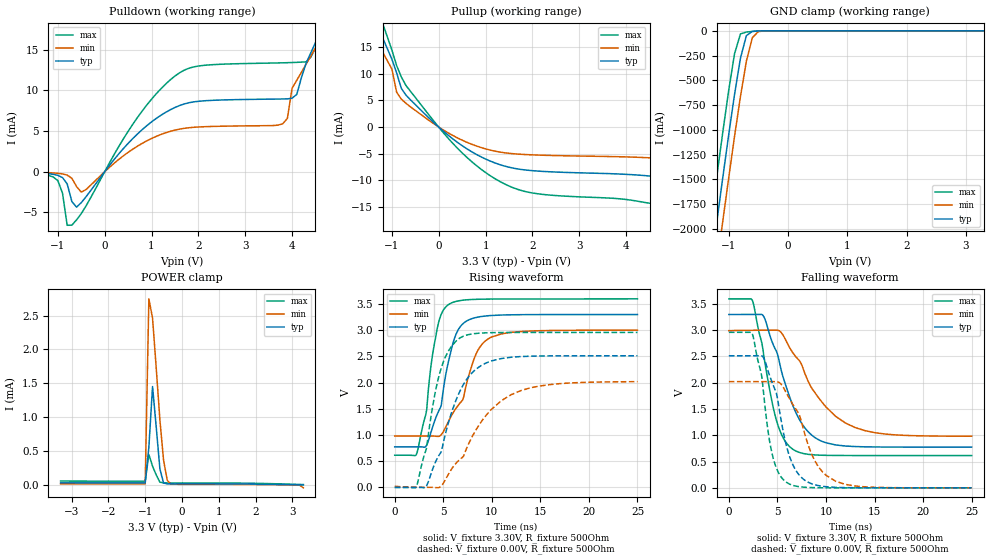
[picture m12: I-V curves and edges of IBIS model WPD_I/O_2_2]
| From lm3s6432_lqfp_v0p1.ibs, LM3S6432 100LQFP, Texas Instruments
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[Model]   WPD_I/O_2_2
Model_type   I/O
Vinl = 1.26
Vinh = 2.04
Vmeas = 1.65
| variable   typ   min   max
C_comp   9.739pF   9.739pF   9.739pF
[Model Spec]
Vinh+   1.91   1.78   2.04
Vinh-   1.90   1.76   2.03
Vinl+   1.40   1.27   1.54
Vinl-   1.39   1.26   1.53
| variable   typ   min   max
[Temperature Range]  25   85   -40
[Voltage Range]   3.3V   3.0V   3.6V
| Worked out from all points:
|   slope of the pulldown table from 0 to 0.495 V, typ, clamps not added: 143 ohm
|   slope of the pullup table from 0 to 0.495 V, typ, clamps not added: 143 ohm
|   GND clamp passes 1 mA (typ) near -0.48 V on its own axis
|   POWER clamp passes 1 mA (typ) near -0.72 V on its own axis
|   falling waveform, V_fixture 3.30V, R_fixture 500Ohm: 20-80 % time 2.91ns typ, 4.35ns min, 1.96ns max; typ from 3.29 V to 0.774 V
|   rising waveform, V_fixture 3.30V, R_fixture 500Ohm: 20-80 % time 1.93ns typ, 2.62ns min, 1.41ns max; typ from 0.774 V to 3.3 V
|   falling waveform, V_fixture 0.00V, R_fixture 500Ohm: 20-80 % time 2ns typ, 2.73ns min, 1.46ns max; typ from 2.51 V to 0 V
|   rising waveform, V_fixture 0.00V, R_fixture 500Ohm: 20-80 % time 2.98ns typ, 4.63ns min, 1.95ns max; typ from 0.002 V to 2.51 V
[Pulldown]
|  Voltage   I(typ)   I(min)   I(max)
-3.3V     -64.09uA   -36.39uA   -91.03uA
-1.1V     -317.9uA   -146.8uA   -640.8uA
-700mV    -3.676mA   -803.4uA   -6.572mA
-500mV    -3.809mA   -2.499mA   -5.157mA
600mV     4.083mA    2.779mA    5.841mA
1.5V      7.907mA    5.122mA    11.78mA
3.8V      8.955mA    5.904mA    13.41mA
4.1V      9.511mA    11.25mA    13.46mA
4.6V      17.19mA    16.24mA    17.17mA
4.8V      19.74mA    18.21mA    20.4mA
6.5V      43.76mA    32.32mA    51.87mA
6.6V      45.45mA    7.601mA    54.4mA
[Pullup]
|  Voltage   I(typ)   I(min)   I(max)
-3.3V     58.75mA    44.68mA    74.87mA
-1.5V     22.86mA    18.91mA    27.02mA
-1.3V     18.84mA    15.71mA    22.06mA
-1.2V     16.81mA    14.1mA     19.54mA
-1V       12.73mA    10.88mA    14.45mA
-900mV    10.17mA    6.552mA    11.54mA
-600mV    5.079mA    3.775mA    6.677mA
500mV     -3.505mA   -2.469mA   -4.866mA
1.5V      -7.548mA   -4.932mA   -11.08mA
5V        -9.793mA   -6.102mA   -15.25mA
5.9V      -11.98mA   -7.296mA   -18.76mA
6.6V      -15.07mA   -8.994mA   -23.96mA
[GND Clamp]
|  Voltage   I(typ)   I(min)   I(max)
-3.3V     -11.72A    -12.12A    -11.3A
-1.4V     -2.845A    -3.285A    -2.387A
-1.3V     -2.39A     -2.831A    -1.93A
-1.2V     -1.938A    -2.38A     -1.478A
-1.1V     -1.494A    -1.934A    -1.036A
-1V       -1.059A    -1.496A    -610.6mA
-900mV    -645mA     -1.069A    -232.9mA
-800mV    -277.1mA   -664.4mA   -31.59mA
-700mV    -48.56mA   -306.6mA   -12.1mA
-600mV    -5.561mA   -70.2mA    -6.281mA
-500mV    -1.172mA   -7.88mA    -2.176mA
3.3V      16.11uA    11.84uA    29.77uA
[POWER Clamp]
|  Voltage   I(typ)   I(min)   I(max)
-3.3V     31.42uA    17.14uA    57.54uA
-1V       30.25uA    16.5uA     55.43uA
-900mV    557.3uA    2.746mA    449.1uA
-800mV    1.452mA    2.463mA    276.5uA
-700mV    854.2uA    1.726mA    147.8uA
-600mV    235.9uA    958.2uA    41.01uA
-500mV    28.31uA    363.4uA    30.71uA
-400mV    16.41uA    67.09uA    29.83uA
-300mV    16.12uA    11.84uA    29.79uA
3.1V      2.408uA    -920.8nA   9.197uA
3.2V      1.227uA    -3.925uA   7.474uA
3.3V      -104.7pA   -42.65uA   5.692uA
[Ramp]
| variable   typ   min   max
dV/dt_f   1.51/2.91n   1.20/4.35n   1.79/1.96n
dV/dt_r   1.50/2.98n   1.20/4.63n   1.77/1.95n
R_load = 500Ohm
[Falling Waveform]
V_fixture = 3.30V
V_fixture_min = 3.00V
V_fixture_max = 3.60V
R_fixture = 500Ohm
|   Time   V(typ)   V(min)   V(max)
0s        3.294V     2.987V     3.591V
2.4ns     3.295V     2.994V     3.572V
3.6ns     3.254V     2.996V     2.513V
4.8ns     2.631V     2.997V     1.352V
5.6ns     2.098V     2.897V     949.6mV
6.6ns     1.561V     2.564V     732.8mV
8.9ns     951.9mV    1.8V       625.2mV
11ns      815.4mV    1.358V     615.6mV
13ns      784.7mV    1.146V     614.4mV
25ns      774.3mV    980.8mV    614.1mV
[Rising Waveform]
V_fixture = 3.30V
V_fixture_min = 3.00V
V_fixture_max = 3.60V
R_fixture = 500Ohm
|   Time   V(typ)   V(min)   V(max)
0s        774.3mV    980mV      614.1mV
2.3ns     774.3mV    980mV      662.6mV
3.3ns     811.2mV    979.9mV    1.493V
3.7ns     1.031V     979.9mV    2.265V
4.4ns     1.404V     973.1mV    3.047V
5.6ns     2.451V     1.283V     3.492V
6.9ns     3.097V     1.645V     3.566V
8.4ns     3.24V      2.553V     3.586V
9.9ns     3.277V     2.86V      3.59V
25ns      3.296V     2.998V     3.594V
[Falling Waveform]
V_fixture = 0.00V
V_fixture_min = 0.00V
V_fixture_max = 0.00V
R_fixture = 500Ohm
|   Time   V(typ)   V(min)   V(max)
0s        2.51V      2.018V     2.956V
2.4ns     2.51V      2.018V     2.935V
3.4ns     2.508V     2.018V     2.101V
4ns       2.248V     2.018V     1.126V
4.5ns     1.983V     2.019V     614.7mV
6ns       749.6mV    1.778V     97.34mV
7.7ns     161.8mV    1.102V     13.05mV
9.1ns     47.3mV     438.1mV    2.734mV
11ns      9.464mV    125mV      429.7uV
25ns      28.08uV    64.98uV    19.55uV
[Rising Waveform]
V_fixture = 0.00V
V_fixture_min = 0.00V
V_fixture_max = 0.00V
R_fixture = 500Ohm
|   Time   V(typ)   V(min)   V(max)
0s        2.15mV     21.52mV    117.9uV
2.2ns     361.2uV    5.666mV    6.533mV
3.2ns     10.4mV     3.134mV    701.8mV
4ns       395.4mV    2.15mV     1.641V
4.7ns     652.8mV    11.9mV     2.22V
5.5ns     1.212V     242.1mV    2.589V
6.7ns     1.829V     533.4mV    2.847V
8.7ns     2.298V     1.195V     2.94V
12ns      2.482V     1.769V     2.954V
25ns      2.51V      2.016V     2.955V
